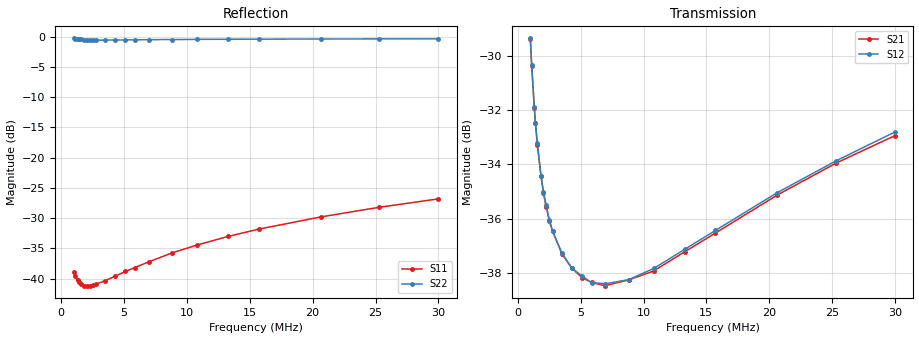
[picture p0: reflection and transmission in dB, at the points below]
! ListType=Log
!!Balun BN43-7051 3.5T
# MHZ S RI R 50
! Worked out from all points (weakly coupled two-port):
!   101 points, 1 MHz to 30 MHz, reference 50 ohm
!   highest |S21| = -29.37 dB at 1 MHz (marker M1); lowest = -38.5 dB at 6.95 MHz (marker M2)
!   lowest |S11| = -41.2 dB at 2.262 MHz (marker M3), VSWR 1.02, Z = 49.9 + j0.864 ohm
!   |S11| at or under -10 dB: start of sweep to end of sweep
!   |S22| runs from -0.5 to -0.3 dB; largest |S21 - S12| = 0.00038
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1  -0.00161 0.0112  0.00883 -0.0328  0.00905 -0.0329  0.9091 0.3399
1.107423  -0.00153 0.0104  0.00908 -0.029  0.00922 -0.029  0.9177 0.3033
1.312713  -0.00155 0.00954  0.00966 -0.0235  0.00978 -0.0235  0.9255 0.2507
1.405116  -0.00152 0.00928  0.00991 -0.0216  0.0101 -0.0216  0.9271 0.2325
1.556058  -0.00151 0.00898  0.0103 -0.0191  0.0105 -0.0192  0.9286 0.2083
1.844513  -0.00145 0.00865  0.0109 -0.0156  0.0109 -0.0156  0.9295 0.1747
2.042657  -0.0013 0.00866  0.0111 -0.0137  0.0112 -0.0138  0.93 0.1579
2.262086  -0.00117 0.00867  0.0114 -0.0121  0.0115 -0.0122  0.9303 0.1433
2.505087  -0.000986 0.0088  0.0115 -0.0107  0.0116 -0.0107  0.9308 0.1305
2.774191  -0.000777 0.00896  0.0117 -0.0094  0.0117 -0.00941  0.9315 0.1191
3.519937  -0.000195 0.00963  0.0118 -0.00679  0.0119 -0.00672  0.934 0.0971
4.316802  0.00055 0.0105  0.0119 -0.00478  0.0119 -0.00477  0.937 0.0819
5.117033  0.00128 0.0114  0.0119 -0.00319  0.012 -0.00317  0.9397 0.071
5.862773  0.002 0.0122  0.0119 -0.00206  0.0119 -0.00201  0.942 0.0629
6.949589  0.00307 0.0134  0.0119 -0.000492  0.012 -0.000457  0.9447 0.0538
8.817746  0.00511 0.0155  0.0121 0.0016  0.0121 0.00171  0.9483 0.0423
10.81396  0.00736 0.0175  0.0122 0.00347  0.0123 0.00361  0.9513 0.0333
13.2621  0.0105 0.0197  0.0126 0.00551  0.0127 0.00565  0.954 0.0247
15.72057  0.0139 0.0216  0.013 0.00729  0.0131 0.00745  0.956 0.0176
20.63659  0.0215 0.0242  0.0141 0.0104  0.0141 0.0107  0.9589 0.00622
25.30843  0.0297 0.0252  0.0152 0.0131  0.0152 0.0134  0.9609 -0.00275
30  0.0387 0.0243  0.0164 0.0155  0.0165 0.0159  0.9623 -0.0109
